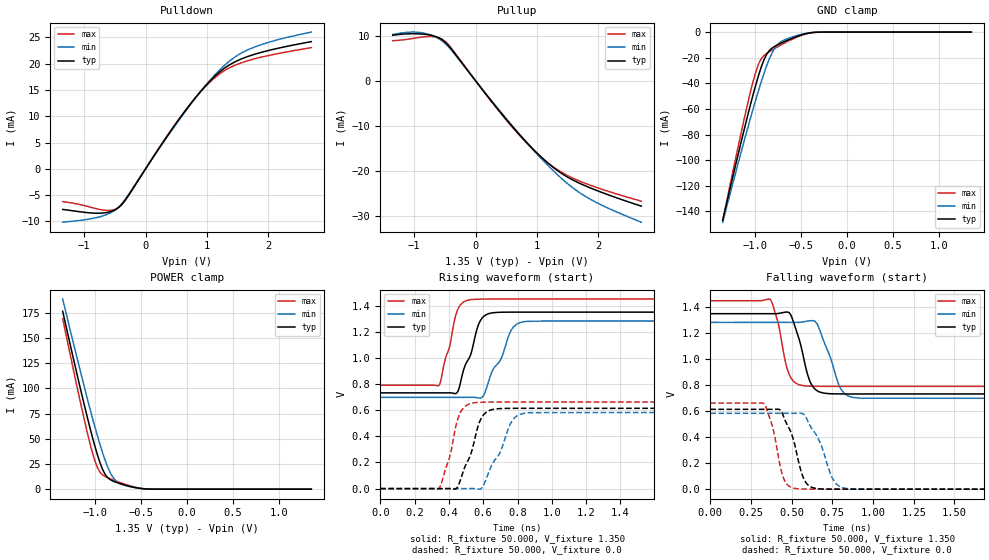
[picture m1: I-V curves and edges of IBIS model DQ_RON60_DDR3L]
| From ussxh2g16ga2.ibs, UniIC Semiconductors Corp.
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|   Model DQ_RON60_DDR3L
[Model] DQ_RON60_DDR3L
Model_type I/O
Vinl =  0.540V
Vinh =  0.810V
Vmeas =  0.675V
Rref =  50.000
Vref =  0.675V
C_comp   0.966pF   0.965pF   0.967pF
[Model Spec]
Vinh   0.810V   0.776V   0.860V
Vinl   0.540V   0.506V   0.590V
Vmeas   0.675V   0.641V   0.725V
Vref   0.675V   0.641V   0.725V
Rref   50.000   NA   NA
[Temperature Range]   25.000   0.105k   -40.000
[Voltage Range]   1.350V   1.283V   1.450V
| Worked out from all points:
|   slope of the pulldown table from 0 to 0.203 V, typ, clamps not added: 55.8 ohm
|   slope of the pullup table from 0 to 0.203 V, typ, clamps not added: 56.9 ohm
|   GND clamp passes 1 mA (typ) near -0.43 V on its own axis
|   POWER clamp passes 1 mA (typ) near -0.52 V on its own axis
|   rising waveform, R_fixture 50.000, V_fixture 1.350: 20-80 % time 89.9ps typ, 118ps min, 71.1ps max; typ from 0.732 V to 1.35 V
|   rising waveform, R_fixture 50.000, V_fixture 0.0: 20-80 % time 92.1ps typ, 119ps min, 75ps max; typ from 0 V to 0.614 V
|   falling waveform, R_fixture 50.000, V_fixture 1.350: 20-80 % time 77.8ps typ, 96.8ps min, 65.8ps max; typ from 1.35 V to 0.732 V
|   falling waveform, R_fixture 50.000, V_fixture 0.0: 20-80 % time 87.7ps typ, 116ps min, 67.6ps max; typ from 0.614 V to 0 V
[Pulldown]
|Voltage   I(typ)   I(min)   I(max)
-1.35V    -7.722mA   -10.15mA   -6.234mA
-735mV    -8.434mA   -9.087mA   -7.75mA
-571mV    -8.147mA   -8.365mA   -7.895mA
-448mV    -7.434mA   -7.38mA    -7.4mA
-325mV    -5.846mA   -5.683mA   -5.893mA
249mV     4.444mA    4.334mA    4.482mA
618mV     10.59mA    10.44mA    10.61mA
905mV     14.83mA    14.81mA    14.73mA
1.151V    17.85mA    18.12mA    17.54mA
1.397V    19.96mA    20.76mA    19.37mA
1.684V    21.43mA    22.71mA    20.61mA
2.7V      24.18mA    25.99mA    23.04mA
[Pullup]
|Voltage   I(typ)   I(min)   I(max)
-1.35V    10.13mA    10.3mA     8.905mA
-908mV    10.43mA    10.74mA    9.653mA
-703mV    10.05mA    10.04mA    9.819mA
-539mV    9.062mA    8.792mA    9.199mA
-416mV    7.422mA    7.162mA    7.626mA
568mV     -9.667mA   -9.558mA   -9.848mA
855mV     -14.05mA   -14.1mA    -14.21mA
1.142V    -17.88mA   -18.33mA   -17.87mA
1.429V    -20.86mA   -22.08mA   -20.57mA
1.757V    -23.19mA   -25.46mA   -22.66mA
2.126V    -25.2mA    -28.13mA   -24.45mA
2.7V      -27.89mA   -31.47mA   -26.78mA
[GND_clamp]
|Voltage   I(typ)   I(min)   I(max)
-1.35V    -146.9mA   -148.4mA   -147.1mA
-1.126V   -78.8mA    -87.41mA   -70.77mA
-1.042V   -54.83mA   -65.59mA   -44.7mA
-986mV    -39.98mA   -51.65mA   -30.01mA
-958mV    -33.17mA   -44.94mA   -24.44mA
-930mV    -26.97mA   -38.48mA   -20.61mA
-874mV    -17.51mA   -26.57mA   -16.72mA
-790mV    -11.36mA   -13.15mA   -13.04mA
-734mV    -9.258mA   -8.444mA   -10.75mA
-510mV    -2.584mA   -1.988mA   -2.931mA
-342mV    -173.6uA   -157.7uA   -187.2uA
1.35V     0A         0A         0A
[POWER_clamp]
|Voltage   I(typ)   I(min)   I(max)
-1.35V    176.6mA    188.8mA    169.4mA
-1.198V   115.5mA    131.6mA    103.2mA
-1.114V   83.04mA    101mA      68.48mA
-1.058V   62.42mA    81.27mA    46.98mA
-1.002V   43.19mA    62.34mA    28.56mA
-946mV    26.54mA    44.62mA    16.92mA
-890mV    14.85mA    28.86mA    12.66mA
-806mV    8.104mA    11.95mA    9.362mA
-750mV    6.207mA    6.646mA    7.386mA
-610mV    2.557mA    2.299mA    3.036mA
-414mV    126.6uA    189uA      94.28uA
1.35V     0A         0A         0A
[Ramp]
| variable   typ   min   max
dV/dt_r   0.369/92.016p   0.350/0.119n   0.397/75.241p
dV/dt_f   0.371/77.557p   0.351/97.020p   0.395/65.845p
R_load = 50.000
[Rising Waveform]
R_fixture= 50.000
V_fixture= 1.350
V_fixture_min= 1.283
V_fixture_max= 1.450
|time   V(typ)   V(min)   V(max)
0s        732.3mV    698mV      791mV
345ps     732.3mV    698mV      794.6mV
448ps     734.1mV    698mV      1.359V
521ps     1.006V     698.4mV    1.444V
570ps     1.246V     693.5mV    1.449V
602ps     1.316V     712.9mV    1.45V
709ps     1.349V     1.008V     1.45V
762ps     1.35V      1.21V      1.45V
819ps     1.35V      1.272V     1.45V
3ns       1.35V      1.283V     1.45V
[Rising Waveform]
R_fixture= 50.000
V_fixture= 0.0
V_fixture_min= 0.0
V_fixture_max= 0.0
|time   V(typ)   V(min)   V(max)
0s        169.2nV    1.818uV    70.74nV
342ps     -22.87uV   3.404uV    391.3uV
403ps     351.9uV    4.048uV    233.7mV
457ps     29.71mV    -16.92uV   551.7mV
543ps     335.5mV    232uV      655.7mV
577ps     504.3mV    -4.401mV   659.9mV
623ps     589.2mV    94.06mV    661.6mV
768ps     614mV      517.7mV    662mV
844ps     614.2mV    577.5mV    662mV
3ns       614.2mV    583.5mV    662mV
[Falling Waveform]
R_fixture= 50.000
V_fixture= 1.350
V_fixture_min= 1.283
V_fixture_max= 1.450
|time   V(typ)   V(min)   V(max)
0s        1.35V      1.283V     1.45V
370ps     1.35V      1.283V     1.457V
417ps     1.351V     1.283V     1.276V
483ps     1.359V     1.283V     888.3mV
569ps     1.037V     1.287V     797mV
610ps     836.1mV    1.295V     792.5mV
643ps     770mV      1.292V     791.5mV
801ps     732.5mV    773.8mV    791mV
877ps     732.3mV    705.8mV    791mV
3ns       732.3mV    698mV      791mV
[Falling Waveform]
R_fixture= 50.000
V_fixture= 0.0
V_fixture_min= 0.0
V_fixture_max= 0.0
|time   V(typ)   V(min)   V(max)
0s        614.2mV    583.5mV    662mV
332ps     614.2mV    583.4mV    656.2mV
385ps     614.2mV    583.4mV    465.3mV
447ps     570.2mV    583.4mV    94.63mV
519ps     342.1mV    583.5mV    6.111mV
566ps     106.2mV    581.9mV    1.056mV
603ps     29.59mV    513.3mV    256.3uV
761ps     100.2uV    59.72mV    732.5nV
834ps     6.939uV    5.603mV    247.7nV
3ns       174.2nV    1.798uV    191.5nV
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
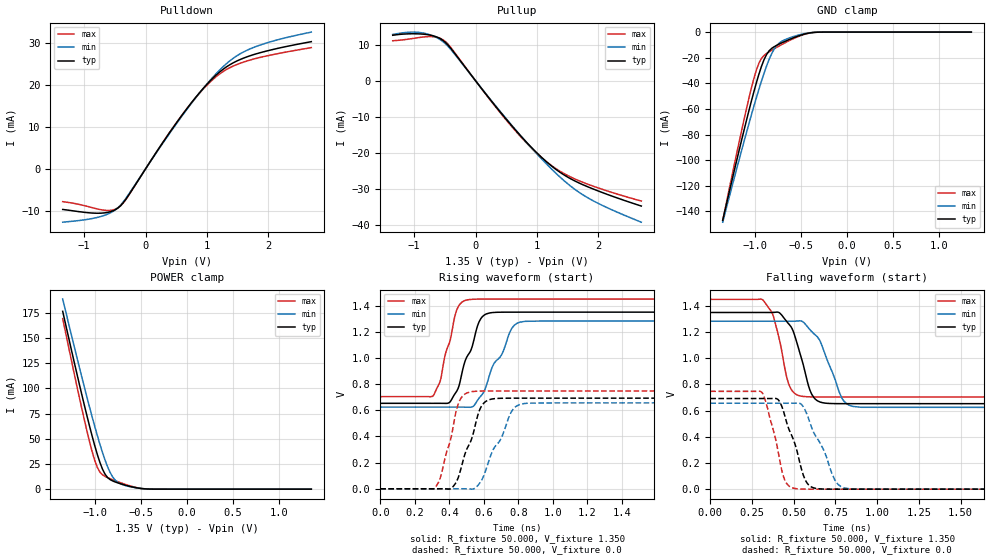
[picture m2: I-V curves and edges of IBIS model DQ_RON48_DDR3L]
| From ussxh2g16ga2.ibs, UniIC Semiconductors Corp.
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|   Model DQ_RON48_DDR3L
[Model] DQ_RON48_DDR3L
Model_type I/O
Vinl =  0.540V
Vinh =  0.810V
Vmeas =  0.675V
Rref =  50.000
Vref =  0.675V
C_comp   0.966pF   0.965pF   0.967pF
[Model Spec]
Vinh   0.810V   0.776V   0.860V
Vinl   0.540V   0.506V   0.590V
Vmeas   0.675V   0.641V   0.725V
Vref   0.675V   0.641V   0.725V
Rref   50.000   NA   NA
[Temperature Range]   25.000   0.105k   -40.000
[Voltage Range]   1.350V   1.283V   1.450V
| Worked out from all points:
|   slope of the pulldown table from 0 to 0.203 V, typ, clamps not added: 44.6 ohm
|   slope of the pullup table from 0 to 0.203 V, typ, clamps not added: 45.5 ohm
|   GND clamp passes 1 mA (typ) near -0.43 V on its own axis
|   POWER clamp passes 1 mA (typ) near -0.52 V on its own axis
|   rising waveform, R_fixture 50.000, V_fixture 1.350: 20-80 % time 98.4ps typ, 133ps min, 76.3ps max; typ from 0.653 V to 1.35 V
|   rising waveform, R_fixture 50.000, V_fixture 0.0: 20-80 % time 99.2ps typ, 131ps min, 79.9ps max; typ from 0 V to 0.693 V
|   falling waveform, R_fixture 50.000, V_fixture 1.350: 20-80 % time 92.2ps typ, 120ps min, 75.9ps max; typ from 1.35 V to 0.653 V
|   falling waveform, R_fixture 50.000, V_fixture 0.0: 20-80 % time 102ps typ, 133ps min, 80.6ps max; typ from 0.693 V to 0 V
[Pulldown]
|Voltage   I(typ)   I(min)   I(max)
-1.35V    -9.661mA   -12.69mA   -7.804mA
-735mV    -10.55mA   -11.36mA   -9.699mA
-571mV    -10.19mA   -10.46mA   -9.878mA
-448mV    -9.296mA   -9.228mA   -9.257mA
-325mV    -7.31mA    -7.106mA   -7.371mA
249mV     5.557mA    5.42mA     5.606mA
618mV     13.25mA    13.06mA    13.27mA
905mV     18.55mA    18.52mA    18.43mA
1.151V    22.32mA    22.66mA    21.94mA
1.397V    24.97mA    25.97mA    24.24mA
1.684V    26.81mA    28.42mA    25.8mA
2.7V      30.25mA    32.53mA    28.84mA
[Pullup]
|Voltage   I(typ)   I(min)   I(max)
-1.35V    12.67mA    12.88mA    11.13mA
-908mV    13.04mA    13.44mA    12.07mA
-703mV    12.57mA    12.56mA    12.28mA
-539mV    11.33mA    11mA       11.5mA
-416mV    9.28mA     8.957mA    9.534mA
568mV     -12.09mA   -11.95mA   -12.31mA
855mV     -17.57mA   -17.63mA   -17.76mA
1.142V    -22.35mA   -22.92mA   -22.34mA
1.429V    -26.07mA   -27.61mA   -25.71mA
1.757V    -28.99mA   -31.84mA   -28.32mA
2.126V    -31.5mA    -35.18mA   -30.55mA
2.7V      -34.86mA   -39.36mA   -33.47mA
[GND_clamp]
|Voltage   I(typ)   I(min)   I(max)
-1.35V    -146.9mA   -148.4mA   -147.1mA
-1.126V   -78.8mA    -87.41mA   -70.77mA
-1.042V   -54.83mA   -65.59mA   -44.7mA
-986mV    -39.98mA   -51.65mA   -30.01mA
-958mV    -33.17mA   -44.94mA   -24.44mA
-930mV    -26.97mA   -38.48mA   -20.61mA
-874mV    -17.51mA   -26.57mA   -16.72mA
-790mV    -11.36mA   -13.15mA   -13.04mA
-734mV    -9.258mA   -8.444mA   -10.75mA
-510mV    -2.584mA   -1.988mA   -2.931mA
-342mV    -173.6uA   -157.7uA   -187.2uA
1.35V     0A         0A         0A
[POWER_clamp]
|Voltage   I(typ)   I(min)   I(max)
-1.35V    176.6mA    188.8mA    169.4mA
-1.198V   115.5mA    131.6mA    103.2mA
-1.114V   83.04mA    101mA      68.48mA
-1.058V   62.42mA    81.27mA    46.98mA
-1.002V   43.19mA    62.34mA    28.56mA
-946mV    26.54mA    44.62mA    16.92mA
-890mV    14.85mA    28.86mA    12.66mA
-806mV    8.104mA    11.95mA    9.362mA
-750mV    6.207mA    6.646mA    7.386mA
-610mV    2.557mA    2.299mA    3.036mA
-414mV    126.6uA    189uA      94.28uA
1.35V     0A         0A         0A
[Ramp]
| variable   typ   min   max
dV/dt_r   0.416/99.045p   0.394/0.131n   0.448/79.809p
dV/dt_f   0.418/92.332p   0.395/0.119n   0.447/75.961p
R_load = 50.000
[Rising Waveform]
R_fixture= 50.000
V_fixture= 1.350
V_fixture_min= 1.283
V_fixture_max= 1.450
|time   V(typ)   V(min)   V(max)
0s        653.2mV    624.1mV    704.3mV
306ps     653.2mV    624.1mV    710.5mV
348ps     653.2mV    624.1mV    827.3mV
406ps     667.2mV    624.1mV    1.141V
443ps     746.1mV    624.1mV    1.367V
508ps     1.022V     623.2mV    1.445V
598ps     1.323V     736.5mV    1.45V
761ps     1.35V      1.225V     1.45V
809ps     1.35V      1.273V     1.45V
3ns       1.35V      1.283V     1.45V
[Rising Waveform]
R_fixture= 50.000
V_fixture= 0.0
V_fixture_min= 0.0
V_fixture_max= 0.0
|time   V(typ)   V(min)   V(max)
0s        157.3nV    1.632uV    72.97nV
316ps     -25.78uV   3.517uV    5.409mV
348ps     124.4uV    5.418uV    85.1mV
426ps     23.88mV    -16.88uV   505.1mV
460ps     120.1mV    115uV      674.6mV
524ps     363.1mV    -2.599mV   740.9mV
606ps     662.7mV    123mV      747.2mV
761ps     692.5mV    592.5mV    747.5mV
825ps     692.6mV    649.9mV    747.5mV
3ns       692.6mV    656.6mV    747.5mV
[Falling Waveform]
R_fixture= 50.000
V_fixture= 1.350
V_fixture_min= 1.283
V_fixture_max= 1.450
|time   V(typ)   V(min)   V(max)
0s        1.35V      1.283V     1.45V
316ps     1.35V      1.283V     1.445V
375ps     1.35V      1.283V     1.332V
426ps     1.333V     1.283V     1.07V
476ps     1.253V     1.283V     784.4mV
544ps     1.009V     1.285V     710.8mV
631ps     685.3mV    1.176V     704.6mV
784ps     653.3mV    706.3mV    704.3mV
855ps     653.2mV    632mV      704.3mV
3ns       653.2mV    624.1mV    704.3mV
[Falling Waveform]
R_fixture= 50.000
V_fixture= 0.0
V_fixture_min= 0.0
V_fixture_max= 0.0
|time   V(typ)   V(min)   V(max)
0s        692.6mV    656.6mV    747.5mV
310ps     692.5mV    656.6mV    739.1mV
412ps     675.2mV    656.6mV    248.7mV
447ps     558.2mV    656.5mV    67.71mV
501ps     367.5mV    656.8mV    6.74mV
546ps     154.3mV    648mV      987.3uV
594ps     26.94mV    519.2mV    121.3uV
746ps     61.4uV     70.46mV    373.6nV
820ps     3.058uV    5.175mV    231.6nV
3ns       139.7nV    1.611uV    188.2nV
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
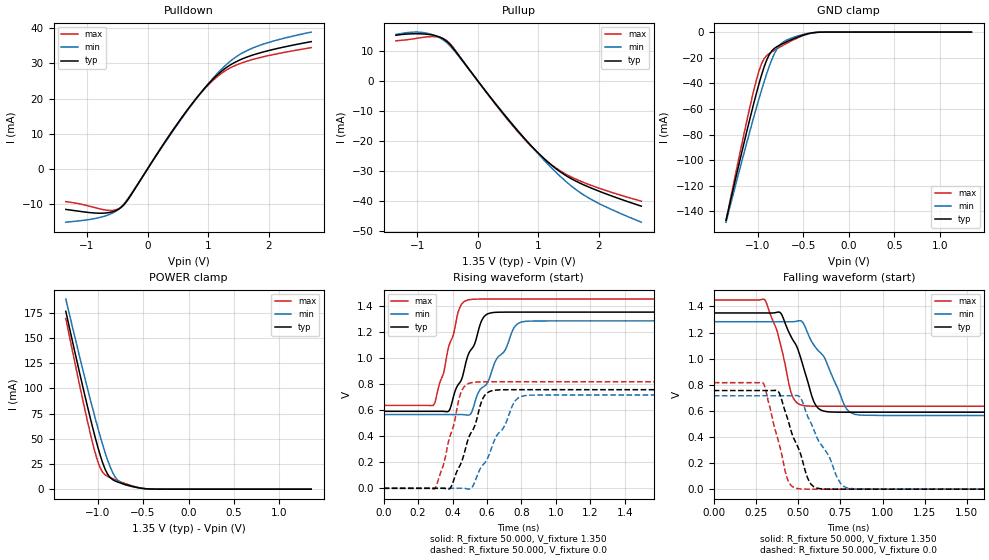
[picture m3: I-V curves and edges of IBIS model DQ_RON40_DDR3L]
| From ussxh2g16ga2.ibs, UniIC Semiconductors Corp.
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|   Model DQ_RON40_DDR3L
[Model] DQ_RON40_DDR3L
Model_type I/O
Vinl =  0.540V
Vinh =  0.810V
Vmeas =  0.675V
Rref =  50.000
Vref =  0.675V
C_comp   0.966pF   0.965pF   0.967pF
[Model Spec]
Vinh   0.810V   0.776V   0.860V
Vinl   0.540V   0.506V   0.590V
Vmeas   0.675V   0.641V   0.725V
Vref   0.675V   0.641V   0.725V
Rref   50.000   NA   NA
[Temperature Range]   25.000   0.105k   -40.000
[Voltage Range]   1.350V   1.283V   1.450V
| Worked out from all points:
|   slope of the pulldown table from 0 to 0.203 V, typ, clamps not added: 37.2 ohm
|   slope of the pullup table from 0 to 0.203 V, typ, clamps not added: 38 ohm
|   GND clamp passes 1 mA (typ) near -0.43 V on its own axis
|   POWER clamp passes 1 mA (typ) near -0.52 V on its own axis
|   rising waveform, R_fixture 50.000, V_fixture 1.350: 20-80 % time 134ps typ, 187ps min, 98.3ps max; typ from 0.59 V to 1.35 V
|   rising waveform, R_fixture 50.000, V_fixture 0.0: 20-80 % time 122ps typ, 172ps min, 89ps max; typ from 0 V to 0.756 V
|   falling waveform, R_fixture 50.000, V_fixture 1.350: 20-80 % time 128ps typ, 178ps min, 95.1ps max; typ from 1.35 V to 0.59 V
|   falling waveform, R_fixture 50.000, V_fixture 0.0: 20-80 % time 119ps typ, 162ps min, 92ps max; typ from 0.756 V to 0 V
[Pulldown]
|Voltage   I(typ)   I(min)   I(max)
-1.35V    -11.58mA   -15.21mA   -9.345mA
-735mV    -12.64mA   -13.62mA   -11.62mA
-571mV    -12.21mA   -12.54mA   -11.84mA
-448mV    -11.14mA   -11.06mA   -11.09mA
-325mV    -8.759mA   -8.516mA   -8.829mA
249mV     6.658mA    6.494mA    6.715mA
618mV     15.87mA    15.65mA    15.89mA
905mV     22.23mA    22.19mA    22.07mA
1.151V    26.74mA    27.15mA    26.28mA
1.397V    29.91mA    31.1mA     29.03mA
1.684V    32.11mA    34.03mA    30.89mA
2.7V      36.23mA    38.94mA    34.53mA
[Pullup]
|Voltage   I(typ)   I(min)   I(max)
-1.35V    15.19mA    15.44mA    13.35mA
-908mV    15.63mA    16.1mA     14.47mA
-703mV    15.07mA    15.05mA    14.72mA
-539mV    13.58mA    13.18mA    13.78mA
-416mV    11.12mA    10.73mA    11.42mA
568mV     -14.48mA   -14.32mA   -14.75mA
855mV     -21.05mA   -21.12mA   -21.28mA
1.142V    -26.78mA   -27.45mA   -26.77mA
1.429V    -31.24mA   -33.08mA   -30.81mA
1.757V    -34.74mA   -38.12mA   -33.95mA
2.126V    -37.73mA   -42.12mA   -36.62mA
2.7V      -41.76mA   -47.11mA   -40.11mA
[GND_clamp]
|Voltage   I(typ)   I(min)   I(max)
-1.35V    -146.9mA   -148.4mA   -147.1mA
-1.126V   -78.8mA    -87.41mA   -70.77mA
-1.042V   -54.83mA   -65.59mA   -44.7mA
-986mV    -39.98mA   -51.65mA   -30.01mA
-958mV    -33.17mA   -44.94mA   -24.44mA
-930mV    -26.97mA   -38.48mA   -20.61mA
-874mV    -17.51mA   -26.57mA   -16.72mA
-790mV    -11.36mA   -13.15mA   -13.04mA
-734mV    -9.258mA   -8.444mA   -10.75mA
-510mV    -2.584mA   -1.988mA   -2.931mA
-342mV    -173.6uA   -157.7uA   -187.2uA
1.35V     0A         0A         0A
[POWER_clamp]
|Voltage   I(typ)   I(min)   I(max)
-1.35V    176.6mA    188.8mA    169.4mA
-1.198V   115.5mA    131.6mA    103.2mA
-1.114V   83.04mA    101mA      68.48mA
-1.058V   62.42mA    81.27mA    46.98mA
-1.002V   43.19mA    62.34mA    28.56mA
-946mV    26.54mA    44.62mA    16.92mA
-890mV    14.85mA    28.86mA    12.66mA
-806mV    8.104mA    11.95mA    9.362mA
-750mV    6.207mA    6.646mA    7.386mA
-610mV    2.557mA    2.299mA    3.036mA
-414mV    126.6uA    189uA      94.28uA
1.35V     0A         0A         0A
[Ramp]
| variable   typ   min   max
dV/dt_r   0.453/0.121n   0.429/0.172n   0.490/88.918p
dV/dt_f   0.456/0.128n   0.431/0.178n   0.489/95.090p
R_load = 50.000
[Rising Waveform]
R_fixture= 50.000
V_fixture= 1.350
V_fixture_min= 1.283
V_fixture_max= 1.450
|time   V(typ)   V(min)   V(max)
0s        589.8mV    564.7mV    635.3mV
288ps     589.8mV    564.7mV    634.2mV
348ps     589.5mV    564.7mV    883.5mV
380ps     594.4mV    564.6mV    1.095V
444ps     813.1mV    565mV      1.39V
495ps     1.036V     560.7mV    1.445V
590ps     1.324V     787.2mV    1.45V
759ps     1.35V      1.234V     1.45V
801ps     1.35V      1.274V     1.45V
3ns       1.35V      1.283V     1.45V
[Rising Waveform]
R_fixture= 50.000
V_fixture= 0.0
V_fixture_min= 0.0
V_fixture_max= 0.0
|time   V(typ)   V(min)   V(max)
0s        148nV      1.482uV    75.27nV
298ps     -65.88uV   3.047uV    -988.3uV
348ps     150.4uV    6.459uV    183.5mV
389ps     5.228mV    -43.88uV   414.7mV
451ps     196.8mV    529.7uV    740.2mV
512ps     434.5mV    4.413mV    810.1mV
601ps     730.8mV    222.5mV    816mV
758ps     755.6mV    658.8mV    816.1mV
817ps     755.6mV    709.7mV    816.1mV
3ns       755.6mV    715.4mV    816.1mV
[Falling Waveform]
R_fixture= 50.000
V_fixture= 1.350
V_fixture_min= 1.283
V_fixture_max= 1.450
|time   V(typ)   V(min)   V(max)
0s        1.35V      1.283V     1.45V
305ps     1.35V      1.283V     1.446V
397ps     1.349V     1.283V     1.102V
463ps     1.156V     1.283V     722mV
527ps     954mV      1.279V     641.8mV
617ps     622.4mV    1.064V     635.4mV
662ps     595.6mV    991.4mV    635.3mV
778ps     589.9mV    633.4mV    635.3mV
840ps     589.8mV    572.2mV    635.3mV
3ns       589.8mV    564.7mV    635.3mV
[Falling Waveform]
R_fixture= 50.000
V_fixture= 0.0
V_fixture_min= 0.0
V_fixture_max= 0.0
|time   V(typ)   V(min)   V(max)
0s        755.6mV    715.4mV    816.1mV
292ps     755.6mV    715.4mV    813.9mV
388ps     737.3mV    715.4mV    343.9mV
442ps     520.4mV    715.2mV    60.7mV
494ps     336mV      717mV      5.299mV
557ps     83.04mV    555.7mV    263.8uV
592ps     19.26mV    459.2mV    46.59uV
752ps     18.68uV    43.03mV    233.6nV
798ps     2.699uV    7.447mV    206.8nV
3ns       95.89nV    1.447uV    147.6nV
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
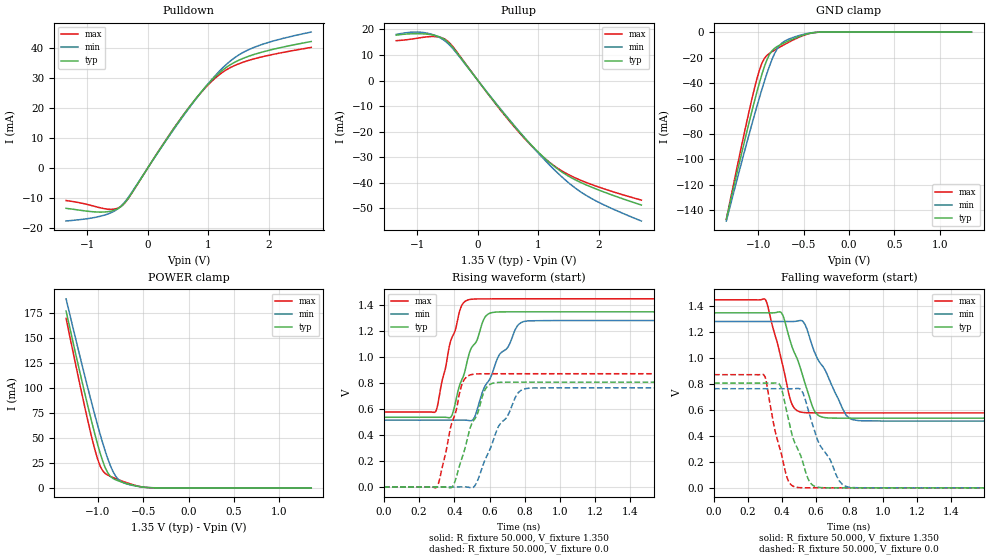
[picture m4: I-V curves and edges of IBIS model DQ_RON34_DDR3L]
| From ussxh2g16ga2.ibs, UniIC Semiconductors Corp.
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|   Model DQ_RON34_DDR3L
[Model] DQ_RON34_DDR3L
Model_type I/O
Vinl =  0.540V
Vinh =  0.810V
Vmeas =  0.675V
Rref =  50.000
Vref =  0.675V
C_comp   0.966pF   0.965pF   0.967pF
[Model Spec]
Vinh   0.810V   0.776V   0.860V
Vinl   0.540V   0.506V   0.590V
Vmeas   0.675V   0.641V   0.725V
Vref   0.675V   0.641V   0.725V
Rref   50.000   NA   NA
[Temperature Range]   25.000   0.105k   -40.000
[Voltage Range]   1.350V   1.283V   1.450V
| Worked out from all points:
|   slope of the pulldown table from 0 to 0.203 V, typ, clamps not added: 31.9 ohm
|   slope of the pullup table from 0 to 0.203 V, typ, clamps not added: 32.6 ohm
|   GND clamp passes 1 mA (typ) near -0.43 V on its own axis
|   POWER clamp passes 1 mA (typ) near -0.52 V on its own axis
|   rising waveform, R_fixture 50.000, V_fixture 1.350: 20-80 % time 128ps typ, 177ps min, 95.8ps max; typ from 0.537 V to 1.35 V
|   rising waveform, R_fixture 50.000, V_fixture 0.0: 20-80 % time 120ps typ, 164ps min, 90.6ps max; typ from 0 V to 0.808 V
|   falling waveform, R_fixture 50.000, V_fixture 1.350: 20-80 % time 125ps typ, 168ps min, 97.5ps max; typ from 1.35 V to 0.537 V
|   falling waveform, R_fixture 50.000, V_fixture 0.0: 20-80 % time 113ps typ, 152ps min, 88.6ps max; typ from 0.808 V to 0 V
[Pulldown]
|Voltage   I(typ)   I(min)   I(max)
-1.35V    -13.51mA   -17.75mA   -10.91mA
-735mV    -14.75mA   -15.89mA   -13.56mA
-571mV    -14.25mA   -14.62mA   -13.81mA
-448mV    -12.99mA   -12.9mA    -12.94mA
-325mV    -10.21mA   -9.929mA   -10.3mA
249mV     7.763mA    7.571mA    7.831mA
618mV     18.51mA    18.24mA    18.54mA
905mV     25.92mA    25.87mA    25.74mA
1.151V    31.18mA    31.65mA    30.65mA
1.397V    34.88mA    36.26mA    33.86mA
1.684V    37.44mA    39.68mA    36.03mA
2.7V      42.25mA    45.41mA    40.28mA
[Pullup]
|Voltage   I(typ)   I(min)   I(max)
-1.35V    17.72mA    18.01mA    15.57mA
-908mV    18.24mA    18.79mA    16.88mA
-703mV    17.58mA    17.56mA    17.17mA
-539mV    15.84mA    15.37mA    16.08mA
-416mV    12.97mA    12.52mA    13.32mA
568mV     -16.88mA   -16.7mA    -17.2mA
855mV     -24.54mA   -24.63mA   -24.81mA
1.142V    -31.21mA   -32.01mA   -31.21mA
1.429V    -36.41mA   -38.57mA   -35.92mA
1.757V    -40.49mA   -44.45mA   -39.57mA
2.126V    -43.98mA   -49.1mA    -42.68mA
2.7V      -48.67mA   -54.92mA   -46.75mA
[GND_clamp]
|Voltage   I(typ)   I(min)   I(max)
-1.35V    -146.9mA   -148.4mA   -147.1mA
-1.126V   -78.8mA    -87.41mA   -70.77mA
-1.042V   -54.83mA   -65.59mA   -44.7mA
-986mV    -39.98mA   -51.65mA   -30.01mA
-958mV    -33.17mA   -44.94mA   -24.44mA
-930mV    -26.97mA   -38.48mA   -20.61mA
-874mV    -17.51mA   -26.57mA   -16.72mA
-790mV    -11.36mA   -13.15mA   -13.04mA
-734mV    -9.258mA   -8.444mA   -10.75mA
-510mV    -2.584mA   -1.988mA   -2.931mA
-342mV    -173.6uA   -157.7uA   -187.2uA
1.35V     0A         0A         0A
[POWER_clamp]
|Voltage   I(typ)   I(min)   I(max)
-1.35V    176.6mA    188.8mA    169.4mA
-1.198V   115.5mA    131.6mA    103.2mA
-1.114V   83.04mA    101mA      68.48mA
-1.058V   62.42mA    81.27mA    46.98mA
-1.002V   43.19mA    62.34mA    28.56mA
-946mV    26.54mA    44.62mA    16.92mA
-890mV    14.85mA    28.86mA    12.66mA
-806mV    8.104mA    11.95mA    9.362mA
-750mV    6.207mA    6.646mA    7.386mA
-610mV    2.557mA    2.299mA    3.036mA
-414mV    126.6uA    189uA      94.28uA
1.35V     0A         0A         0A
[Ramp]
| variable   typ   min   max
dV/dt_r   0.485/0.120n   0.459/0.164n   0.524/90.705p
dV/dt_f   0.488/0.125n   0.461/0.169n   0.523/97.430p
R_load = 50.000
[Rising Waveform]
R_fixture= 50.000
V_fixture= 1.350
V_fixture_min= 1.283
V_fixture_max= 1.450
|time   V(typ)   V(min)   V(max)
0s        537.3mV    515.3mV    578mV
293ps     537.3mV    515.3mV    580mV
388ps     557.1mV    515.3mV    1.158V
440ps     819.3mV    515.7mV    1.393V
485ps     1.032V     511.7mV    1.445V
515ps     1.102V     538.3mV    1.449V
589ps     1.33V      806.9mV    1.45V
657ps     1.349V     1.023V     1.45V
796ps     1.35V      1.276V     1.45V
3ns       1.35V      1.283V     1.45V
[Rising Waveform]
R_fixture= 50.000
V_fixture= 0.0
V_fixture_min= 0.0
V_fixture_max= 0.0
|time   V(typ)   V(min)   V(max)
0s        140.3nV    1.358uV    76.88nV
299ps     -79.46uV   3.434uV    -2.765mV
391ps     5.823mV    -51.77uV   514.9mV
443ps     222mV      476.2uV    790.7mV
496ps     478.8mV    -6.374mV   865.7mV
589ps     777.7mV    251.2mV    872.8mV
650ps     805.9mV    465.9mV    872.8mV
755ps     807.9mV    712.1mV    872.9mV
809ps     807.9mV    759.2mV    872.9mV
3ns       807.9mV    764.5mV    872.9mV
[Falling Waveform]
R_fixture= 50.000
V_fixture= 1.350
V_fixture_min= 1.283
V_fixture_max= 1.450
|time   V(typ)   V(min)   V(max)
0s        1.35V      1.283V     1.45V
301ps     1.35V      1.283V     1.455V
401ps     1.344V     1.283V     971.7mV
455ps     1.112V     1.283V     663.4mV
514ps     908mV      1.291V     584.1mV
580ps     631.8mV    1.096V     578.3mV
613ps     562.1mV    991.6mV    578mV
781ps     537.3mV    559.5mV    578mV
816ps     537.3mV    526.9mV    578mV
3ns       537.3mV    515.3mV    578mV
[Falling Waveform]
R_fixture= 50.000
V_fixture= 0.0
V_fixture_min= 0.0
V_fixture_max= 0.0
|time   V(typ)   V(min)   V(max)
0s        807.9mV    764.5mV    872.9mV
293ps     807.9mV    764.5mV    873mV
389ps     794.2mV    764.5mV    302.7mV
435ps     555.7mV    764.3mV    65.69mV
480ps     339.3mV    765.4mV    6.623mV
524ps     201.1mV    734.8mV    655.2uV
581ps     22.4mV     493.8mV    36.04uV
740ps     16.26uV    53.4mV     223.6nV
791ps     1.886uV    6.829mV    199.3nV
3ns       78.32nV    1.307uV    130.3nV
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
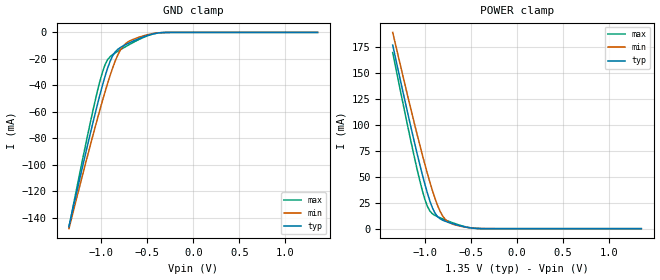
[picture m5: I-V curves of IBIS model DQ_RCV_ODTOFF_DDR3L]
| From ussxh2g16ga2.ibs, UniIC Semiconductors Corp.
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|   Model DQ_RCV_ODTOFF_DDR3L
[Model] DQ_RCV_ODTOFF_DDR3L
Model_type Input
Vinl =  0.540V
Vinh =  0.810V
C_comp   0.966pF   0.965pF   0.967pF
[Model Spec]
Vinh   0.810V   0.776V   0.860V
Vinl   0.540V   0.506V   0.590V
[Temperature Range]   25.000   0.105k   -40.000
[Voltage Range]   1.350V   1.283V   1.450V
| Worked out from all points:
|   GND clamp passes 1 mA (typ) near -0.43 V on its own axis
|   POWER clamp passes 1 mA (typ) near -0.52 V on its own axis
[GND_clamp]
|Voltage   I(typ)   I(min)   I(max)
-1.35V    -146.9mA   -148.4mA   -147.1mA
-1.126V   -78.8mA    -87.41mA   -70.77mA
-1.042V   -54.83mA   -65.59mA   -44.7mA
-986mV    -39.98mA   -51.65mA   -30.01mA
-958mV    -33.17mA   -44.94mA   -24.44mA
-930mV    -26.97mA   -38.48mA   -20.61mA
-874mV    -17.51mA   -26.57mA   -16.72mA
-790mV    -11.36mA   -13.15mA   -13.04mA
-734mV    -9.258mA   -8.444mA   -10.75mA
-510mV    -2.584mA   -1.988mA   -2.931mA
-342mV    -173.6uA   -157.7uA   -187.2uA
1.35V     0A         0A         0A
[POWER_clamp]
|Voltage   I(typ)   I(min)   I(max)
-1.35V    176.6mA    188.8mA    169.4mA
-1.198V   115.5mA    131.6mA    103.2mA
-1.114V   83.04mA    101mA      68.48mA
-1.058V   62.42mA    81.27mA    46.98mA
-1.002V   43.19mA    62.34mA    28.56mA
-946mV    26.54mA    44.62mA    16.92mA
-890mV    14.85mA    28.86mA    12.66mA
-806mV    8.104mA    11.95mA    9.362mA
-750mV    6.207mA    6.646mA    7.386mA
-610mV    2.557mA    2.299mA    3.036mA
-414mV    126.6uA    189uA      94.28uA
1.35V     0A         0A         0A
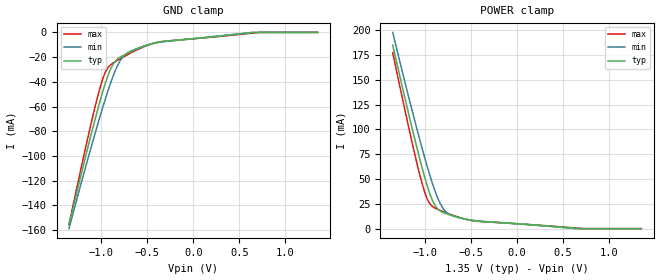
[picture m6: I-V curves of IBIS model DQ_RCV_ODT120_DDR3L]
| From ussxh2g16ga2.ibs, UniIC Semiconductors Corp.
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|   Model DQ_RCV_ODT120_DDR3L
[Model] DQ_RCV_ODT120_DDR3L
Model_type Input
Vinl =  0.540V
Vinh =  0.810V
C_comp   0.966pF   0.965pF   0.967pF
[Model Spec]
Vinh   0.810V   0.776V   0.860V
Vinl   0.540V   0.506V   0.590V
[Temperature Range]   25.000   0.105k   -40.000
[Voltage Range]   1.350V   1.283V   1.450V
[GND_clamp]
|Voltage   I(typ)   I(min)   I(max)
-1.35V    -155.9mA   -158.8mA   -155.5mA
-1.126V   -87.57mA   -97.4mA    -79.03mA
-1.042V   -63.53mA   -75.42mA   -52.94mA
-986mV    -48.64mA   -61.38mA   -38.23mA
-930mV    -35.58mA   -48.1mA    -28.81mA
-874mV    -26.06mA   -36.07mA   -24.91mA
-790mV    -19.82mA   -22.46mA   -21.2mA
-734mV    -17.64mA   -17.62mA   -18.89mA
-482mV    -9.816mA   -9.854mA   -10.03mA
-314mV    -7.175mA   -7.488mA   -7.205mA
638mV     -251.5uA   -10.74uA   -660.9uA
1.35V     0A         0A         0A
[POWER_clamp]
|Voltage   I(typ)   I(min)   I(max)
-1.35V    185.2mA    197.9mA    177.4mA
-1.114V   91.62mA    110.1mA    76.53mA
-1.058V   70.97mA    90.31mA    55.03mA
-1.002V   51.7mA     71.35mA    36.61mA
-946mV    35.02mA    53.58mA    24.97mA
-890mV    23.28mA    37.75mA    20.71mA
-806mV    16.46mA    20.72mA    17.4mA
-750mV    14.5mA     15.31mA    15.4mA
-610mV    10.6mA     10.63mA    10.91mA
-414mV    7.452mA    7.718mA    7.336mA
650mV     229.5uA    0A         552.3uA
1.35V     0A         0A         0A
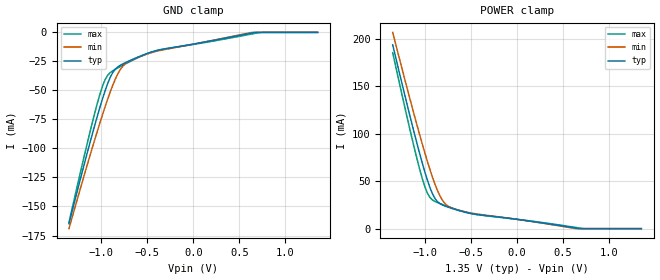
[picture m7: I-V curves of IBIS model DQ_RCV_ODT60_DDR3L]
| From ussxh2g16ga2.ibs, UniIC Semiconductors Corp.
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|   Model DQ_RCV_ODT60_DDR3L
[Model] DQ_RCV_ODT60_DDR3L
Model_type Input
Vinl =  0.540V
Vinh =  0.810V
C_comp   0.966pF   0.965pF   0.967pF
[Model Spec]
Vinh   0.810V   0.776V   0.860V
Vinl   0.540V   0.506V   0.590V
[Temperature Range]   25.000   0.105k   -40.000
[Voltage Range]   1.350V   1.283V   1.450V
[GND_clamp]
|Voltage   I(typ)   I(min)   I(max)
-1.35V    -164.8mA   -169.1mA   -163.9mA
-1.126V   -96.3mA    -107.3mA   -87.26mA
-1.042V   -72.2mA    -85.17mA   -61.14mA
-986mV    -57.26mA   -71.02mA   -46.41mA
-930mV    -44.15mA   -57.63mA   -36.98mA
-874mV    -34.58mA   -45.49mA   -33.06mA
-790mV    -28.24mA   -31.69mA   -29.33mA
-734mV    -25.99mA   -26.72mA   -26.99mA
-594mV    -21.06mA   -21.25mA   -21.53mA
-370mV    -15.11mA   -15.75mA   -15.17mA
638mV     -505uA     -16.1uA    -1.331mA
1.35V     0A         0A         0A
[POWER_clamp]
|Voltage   I(typ)   I(min)   I(max)
-1.35V    193.8mA    206.9mA    185.5mA
-1.226V   143.7mA    160.1mA    131.2mA
-1.114V   100.1mA    119mA      84.5mA
-1.058V   79.44mA    99.26mA    63mA
-1.002V   60.15mA    80.25mA    44.58mA
-946mV    43.43mA    62.43mA    32.94mA
-890mV    31.65mA    46.55mA    28.68mA
-806mV    24.74mA    29.39mA    25.35mA
-750mV    22.71mA    23.89mA    23.33mA
-470mV    15.53mA    16.01mA    15.32mA
650mV     454.3uA    0A         1.087mA
1.35V     0A         0A         0A
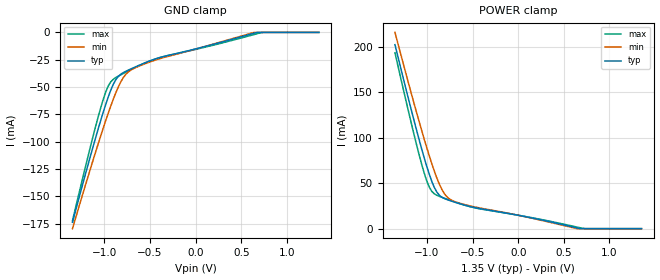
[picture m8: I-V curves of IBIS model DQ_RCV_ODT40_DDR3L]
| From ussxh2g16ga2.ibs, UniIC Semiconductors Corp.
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|   Model DQ_RCV_ODT40_DDR3L
[Model] DQ_RCV_ODT40_DDR3L
Model_type Input
Vinl =  0.540V
Vinh =  0.810V
C_comp   0.966pF   0.965pF   0.967pF
[Model Spec]
Vinh   0.810V   0.776V   0.860V
Vinl   0.540V   0.506V   0.590V
[Temperature Range]   25.000   0.105k   -40.000
[Voltage Range]   1.350V   1.283V   1.450V
[GND_clamp]
|Voltage   I(typ)   I(min)   I(max)
-1.35V    -173.6mA   -179.4mA   -172.2mA
-1.126V   -105mA     -117.2mA   -95.48mA
-1.042V   -80.84mA   -94.93mA   -69.32mA
-986mV    -65.85mA   -80.67mA   -54.58mA
-930mV    -52.69mA   -67.17mA   -45.13mA
-874mV    -43.07mA   -54.92mA   -41.2mA
-790mV    -36.63mA   -40.93mA   -37.44mA
-734mV    -34.31mA   -35.83mA   -35.08mA
-398mV    -23.11mA   -24.14mA   -23.19mA
638mV     -757.9uA   -31.51uA   -1.992mA
750mV     0A         0A         0A
1.35V     0A         0A         0A
[POWER_clamp]
|Voltage   I(typ)   I(min)   I(max)
-1.35V    202.4mA    215.9mA    193.5mA
-1.114V   108.6mA    128mA      92.51mA
-1.058V   87.93mA    108.2mA    71mA
-1.002V   68.6mA     89.19mA    52.58mA
-946mV    51.85mA    71.31mA    40.95mA
-890mV    40.02mA    55.37mA    36.68mA
-806mV    33.04mA    38.09mA    33.34mA
-750mV    30.94mA    32.48mA    31.29mA
-470mV    23.05mA    23.75mA    22.77mA
650mV     678.6uA    0A         1.63mA
734mV     0A         0A         0A
1.35V     0A         0A         0A
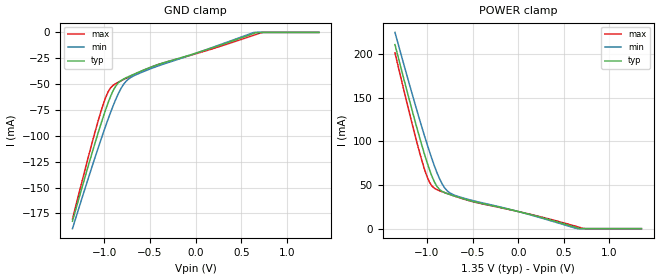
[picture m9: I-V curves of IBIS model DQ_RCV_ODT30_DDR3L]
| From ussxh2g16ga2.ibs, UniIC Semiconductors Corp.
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|   Model DQ_RCV_ODT30_DDR3L
[Model] DQ_RCV_ODT30_DDR3L
Model_type Input
Vinl =  0.540V
Vinh =  0.810V
C_comp   0.966pF   0.965pF   0.967pF
[Model Spec]
Vinh   0.810V   0.776V   0.860V
Vinl   0.540V   0.506V   0.590V
[Temperature Range]   25.000   0.105k   -40.000
[Voltage Range]   1.350V   1.283V   1.450V
[GND_clamp]
|Voltage   I(typ)   I(min)   I(max)
-1.35V    -182.5mA   -189.7mA   -180.5mA
-1.126V   -113.8mA   -127.1mA   -103.7mA
-1.042V   -89.53mA   -104.7mA   -77.55mA
-986mV    -74.5mA    -90.33mA   -62.79mA
-930mV    -61.28mA   -76.72mA   -53.33mA
-874mV    -51.6mA    -64.35mA   -49.38mA
-790mV    -45.08mA   -50.18mA   -45.59mA
-734mV    -42.68mA   -44.94mA   -43.21mA
-398mV    -30.63mA   -32.01mA   -30.71mA
638mV     -1.014mA   -39.78uA   -2.669mA
750mV     0A         0A         0A
1.35V     0A         0A         0A
[POWER_clamp]
|Voltage   I(typ)   I(min)   I(max)
-1.35V    210.9mA    224.9mA    201.5mA
-1.142V   127.8mA    147.1mA    111.8mA
-1.058V   96.41mA    117.2mA    78.98mA
-1.002V   77.05mA    98.1mA     60.56mA
-946mV    60.26mA    80.18mA    48.93mA
-890mV    48.39mA    64.17mA    44.66mA
-834mV    42.78mA    51.41mA    42.35mA
-778mV    40.18mA    43.39mA    40.25mA
-610mV    34.54mA    35.37mA    34.32mA
650mV     900.4uA    0A         2.158mA
734mV     0A         0A         0A
1.35V     0A         0A         0A
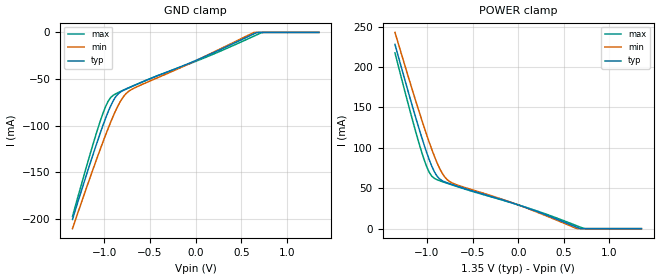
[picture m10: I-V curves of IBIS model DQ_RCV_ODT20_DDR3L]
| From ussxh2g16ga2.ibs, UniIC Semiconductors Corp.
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|   Model DQ_RCV_ODT20_DDR3L
[Model] DQ_RCV_ODT20_DDR3L
Model_type Input
Vinl =  0.540V
Vinh =  0.810V
C_comp   0.966pF   0.965pF   0.967pF
[Model Spec]
Vinh   0.810V   0.776V   0.860V
Vinl   0.540V   0.506V   0.590V
[Temperature Range]   25.000   0.105k   -40.000
[Voltage Range]   1.350V   1.283V   1.450V
[GND_clamp]
|Voltage   I(typ)   I(min)   I(max)
-1.35V    -200.3mA   -210.2mA   -197.2mA
-1.098V   -122.9mA   -139.2mA   -111.1mA
-1.042V   -106.8mA   -124.2mA   -93.91mA
-986mV    -91.68mA   -109.6mA   -79.12mA
-930mV    -78.37mA   -95.76mA   -69.63mA
-874mV    -68.58mA   -83.16mA   -65.65mA
-790mV    -61.86mA   -68.62mA   -61.81mA
-734mV    -59.32mA   -63.1mA    -59.38mA
22mV      -29.21mA   -29.28mA   -30.16mA
638mV     -1.516mA   -57.51uA   -3.995mA
750mV     0A         0A         0A
1.35V     0A         0A         0A
[POWER_clamp]
|Voltage   I(typ)   I(min)   I(max)
-1.35V    228mA      242.9mA    217.5mA
-1.114V   134.1mA    155mA      116.4mA
-1.002V   93.94mA    115.9mA    76.52mA
-946mV    77.08mA    97.91mA    64.89mA
-890mV    65.12mA    81.77mA    60.62mA
-834mV    59.4mA     68.85mA    58.3mA
-778mV    56.69mA    60.65mA    56.16mA
-666mV    52.5mA     53.95mA    51.97mA
62mV      27.02mA    26.77mA    27.23mA
650mV     1.352mA    0A         3.235mA
734mV     0A         0A         0A
1.35V     0A         0A         0A
